! (c) 2009  Infineon Technologies AG, Munich
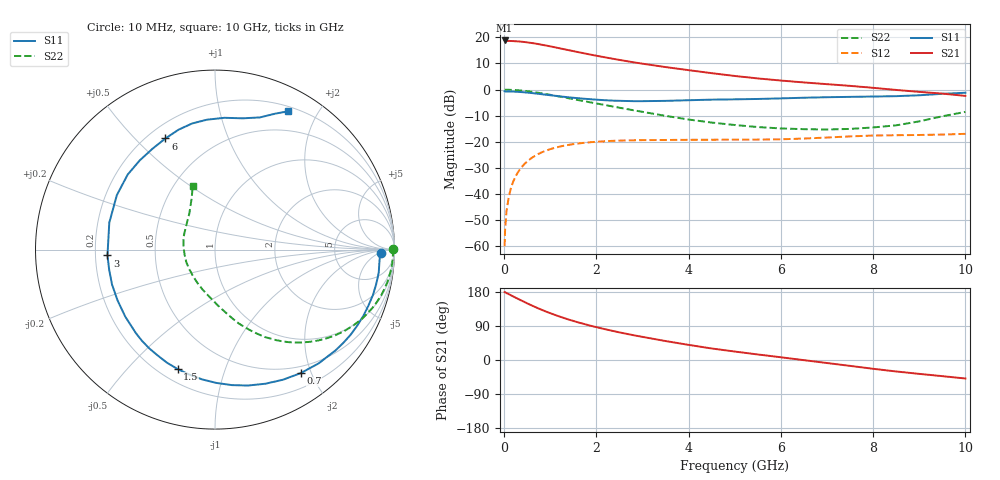
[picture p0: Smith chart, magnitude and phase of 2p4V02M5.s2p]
! Infineon Technologies  Discrete & RF Semiconductors
! BFP420
! VCE =  4.0 V,  IC =  2.5 mA
! Common Emitter S-Parameters:  Nov 2009
# GHz  S  MA  R  50
!  f  S11  S21  S12  S22
! GHz  MAG  ANG  MAG  ANG  MAG  ANG  MAG  ANG
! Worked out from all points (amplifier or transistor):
!   46 points, 10 MHz to 10 GHz, reference 50 ohm
!   highest |S21| = 18.8 dB at 10 MHz (marker M1)
!   |S21| within 3 dB of that: start of sweep to 1.202 GHz
!   unconditionally stable (mu >= 1): 3.734 GHz to end of sweep
!   at 300 MHz: K = 0.07, MSG = 25.1 dB, |S12| = -31.7 dB
!   at 1.7 GHz: K = 0.39, MSG = 17.2 dB, |S12| = -20.5 dB
!   at 10 GHz: K = 1.19, MAG = 4.6 dB, |S12| = -17.0 dB
!   lowest NFmin = 0.55 dB at 900 MHz
!   S11 on the Smith chart (normalised r, x): 10 MHz: 24, -7; 700 MHz: 0.40, -1.85; 1.5 GHz: 0.27, -0.70; 3 GHz: 0.25, -0.03; 6 GHz: 0.27, +0.62; 10 GHz: 0.26, +1.62
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0.01  0.926 -1.2  8.733 179.1  0.001 61.6  0.9905 0.1
0.02  0.9208 -1.7  8.49 178.9  0.002 73.2  0.9912 -0.8
0.05  0.9185 -4.0  8.509 176.7  0.0046 80.0  0.9917 -2.1
0.15  0.9184 -12.2  8.529 170.6  0.0133 80.8  0.9869 -6.5
0.3  0.9051 -24.2  8.379 161.4  0.0261 75.4  0.9695 -13.0
0.45  0.8837 -36.1  8.131 152.5  0.0383 69.4  0.9422 -19.2
0.6  0.8577 -47.6  7.801 143.8  0.0493 63.3  0.9064 -25.1
0.7  0.8378 -55.2  7.556 138.4  0.0559 59.5  0.8795 -28.7
1  0.7792 -76.4  6.729 123.5  0.0723 49.3  0.7933 -38.6
1.2  0.7429 -89.4  6.189 114.7  0.0807 43.4  0.736 -44.3
1.5  0.6971 -107.4  5.458 103.1  0.0902 35.8  0.6555 -51.8
1.7  0.6706 -118.5  5.028 96.1  0.0949 31.4  0.6072 -56.1
2.2  0.6241 -143.2  4.128 80.9  0.1026 22.5  0.5031 -65.3
2.6  0.6059 -161.2  3.576 70.3  0.1059 16.7  0.4327 -72.1
3  0.6 -176.9  3.133 61.0  0.1076 12.2  0.3747 -78.1
3.5  0.6078 165.7  2.7 50.0  0.1083 7.6  0.3136 -86.7
4.5  0.6415 139.3  2.063 30.4  0.1094 1.5  0.2334 -107.2
5.5  0.6611 121.8  1.636 14.6  0.1101 -2.0  0.1916 -129.8
6  0.6782 114.0  1.49 7.2  0.1116 -2.8  0.18 -143.0
7  0.7142 100.3  1.27 -8.0  0.1206 -5.1  0.1717 -170.4
8.5  0.7478 78.0  0.984 -30.3  0.1336 -14.2  0.2066 141.6
10  0.8695 62.3  0.758 -48.8  0.1419 -20.1  0.3738 109.3
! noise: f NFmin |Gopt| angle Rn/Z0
0.9  0.55  0.41  33  0.2
1.8  1.02  0.24  78  0.16
2.4  1.11  0.26  103  0.15
3  1.28  0.27  140  0.11
4  1.5  0.34  -163  0.1
5  1.85  0.4  -130  0.26
6  2.56  0.5  -109  0.35
